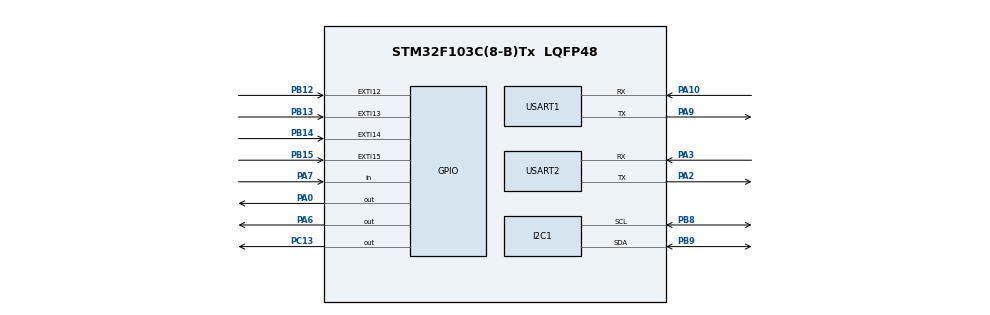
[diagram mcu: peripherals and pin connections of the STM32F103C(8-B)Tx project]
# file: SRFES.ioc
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Dma.Request0=USART1_RX
Dma.Request1=USART1_TX
Dma.Request2=USART2_TX
Dma.Request3=USART2_RX
Dma.USART1_RX.0.Direction=DMA_PERIPH_TO_MEMORY
Dma.USART1_RX.0.Instance=DMA1_Channel5
Dma.USART1_RX.0.MemDataAlignment=DMA_MDATAALIGN_BYTE
Dma.USART1_RX.0.MemInc=DMA_MINC_ENABLE
Dma.USART1_RX.0.Mode=DMA_CIRCULAR
Dma.USART1_RX.0.PeriphDataAlignment=DMA_PDATAALIGN_BYTE
Dma.USART1_RX.0.PeriphInc=DMA_PINC_DISABLE
Dma.USART1_RX.0.Priority=DMA_PRIORITY_HIGH
Dma.USART1_TX.1.Direction=DMA_MEMORY_TO_PERIPH
Dma.USART1_TX.1.Instance=DMA1_Channel4
Dma.USART1_TX.1.MemDataAlignment=DMA_MDATAALIGN_BYTE
Dma.USART1_TX.1.MemInc=DMA_MINC_ENABLE
Dma.USART1_TX.1.Mode=DMA_NORMAL
Dma.USART1_TX.1.PeriphDataAlignment=DMA_PDATAALIGN_BYTE
Dma.USART1_TX.1.PeriphInc=DMA_PINC_DISABLE
Dma.USART1_TX.1.Priority=DMA_PRIORITY_HIGH
Dma.USART2_RX.3.Direction=DMA_PERIPH_TO_MEMORY
Dma.USART2_RX.3.Instance=DMA1_Channel6
Dma.USART2_RX.3.MemDataAlignment=DMA_MDATAALIGN_BYTE
Dma.USART2_RX.3.MemInc=DMA_MINC_ENABLE
Dma.USART2_RX.3.Mode=DMA_CIRCULAR
Dma.USART2_RX.3.PeriphDataAlignment=DMA_PDATAALIGN_BYTE
Dma.USART2_RX.3.PeriphInc=DMA_PINC_DISABLE
Dma.USART2_RX.3.Priority=DMA_PRIORITY_MEDIUM
Dma.USART2_TX.2.Direction=DMA_MEMORY_TO_PERIPH
Dma.USART2_TX.2.Instance=DMA1_Channel7
Dma.USART2_TX.2.MemDataAlignment=DMA_MDATAALIGN_BYTE
Dma.USART2_TX.2.MemInc=DMA_MINC_ENABLE
Dma.USART2_TX.2.Mode=DMA_NORMAL
Dma.USART2_TX.2.PeriphDataAlignment=DMA_PDATAALIGN_BYTE
Dma.USART2_TX.2.PeriphInc=DMA_PINC_DISABLE
Dma.USART2_TX.2.Priority=DMA_PRIORITY_MEDIUM
I2C1.I2C_Mode=I2C_Fast
Mcu.Family=STM32F1
Mcu.Name=STM32F103C(8-B)Tx
Mcu.Package=LQFP48
NVIC.DMA1_Channel4_IRQn=true\:0\:0\:false\:false\:true\:false\:true\:true
NVIC.DMA1_Channel5_IRQn=true\:0\:0\:false\:false\:true\:false\:true\:true
NVIC.DMA1_Channel6_IRQn=true\:0\:0\:false\:false\:true\:false\:true\:true
NVIC.DMA1_Channel7_IRQn=true\:0\:0\:false\:false\:true\:false\:true\:true
NVIC.EXTI15_10_IRQn=true\:1\:0\:true\:false\:true\:true\:true\:true
NVIC.PriorityGroup=NVIC_PRIORITYGROUP_4
NVIC.TIM2_IRQn=true\:2\:0\:true\:false\:true\:true\:true\:true
NVIC.USART1_IRQn=true\:0\:0\:false\:false\:true\:true\:true\:true
NVIC.USART2_IRQn=true\:0\:0\:false\:false\:true\:true\:true\:true
PA0-WKUP.Signal=GPIO_Output
PA10.Mode=Asynchronous
PA10.Signal=USART1_RX
PA13.Mode=Serial_Wire
PA13.Signal=SYS_JTMS-SWDIO
PA14.Mode=Serial_Wire
PA14.Signal=SYS_JTCK-SWCLK
PA2.Mode=Asynchronous
PA2.Signal=USART2_TX
PA3.Mode=Asynchronous
PA3.Signal=USART2_RX
PA6.Signal=GPIO_Output
PA7.GPIO_PuPd=GPIO_PULLUP
PA7.Signal=GPIO_Input
PA9.Mode=Asynchronous
PA9.Signal=USART1_TX
PB12.GPIO_ModeDefaultEXTI=GPIO_MODE_IT_FALLING
PB12.GPIO_PuPd=GPIO_PULLUP
PB12.Signal=GPXTI12
PB13.GPIO_ModeDefaultEXTI=GPIO_MODE_IT_FALLING
PB13.GPIO_PuPd=GPIO_PULLUP
PB13.Signal=GPXTI13
PB14.GPIO_ModeDefaultEXTI=GPIO_MODE_IT_FALLING
PB14.GPIO_PuPd=GPIO_PULLUP
PB14.Signal=GPXTI14
PB15.GPIO_ModeDefaultEXTI=GPIO_MODE_IT_FALLING
PB15.GPIO_PuPd=GPIO_PULLUP
PB15.Signal=GPXTI15
PB8.GPIO_Speed=GPIO_SPEED_FREQ_LOW
PB8.Mode=I2C
PB8.Signal=I2C1_SCL
PB9.GPIO_Speed=GPIO_SPEED_FREQ_LOW
PB9.Mode=I2C
PB9.Signal=I2C1_SDA
PC13-TAMPER-RTC.PinState=GPIO_PIN_SET
PC13-TAMPER-RTC.Signal=GPIO_Output
ProjectManager.HeapSize=0x200
ProjectManager.StackSize=0x400
ProjectManager.TargetToolchain=CMake
RCC.APB1Freq_Value=8000000
RCC.APB2Freq_Value=8000000
TIM2.AutoReloadPreload=TIM_AUTORELOAD_PRELOAD_ENABLE
TIM2.Period=999
TIM2.Prescaler=719
USART1.VirtualMode=VM_ASYNC
USART2.VirtualMode=VM_ASYNC
VP_TIM2_VS_ClockSourceINT.Mode=Internal
board=custom

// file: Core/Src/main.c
/* USER CODE BEGIN Header */
/**
  ******************************************************************************
  * @file           : main.c
  * @brief          : 生鲜结算系统主入口 —— 模块编排器
  *                   所有业务逻辑分散在独立模块中：
  *                     buzzer.c 蜂鸣器 / alarm.c 报警 / led.c 心跳灯
  *                     oled.c 显示 / key.c 按键 / sensor.c 称重
  ******************************************************************************
  */
/* USER CODE END Header */
#include "main.h"
#include "dma.h"
#include "i2c.h"
#include "tim.h"
#include "usart.h"
#include "gpio.h"

/* USER CODE BEGIN Includes */
#include "oled.h"
#include "key.h"
#include "sensor.h"
#include "buzzer.h"
#include "alarm.h"
#include "led.h"
#include "voice.h"
#include "bluetooth.h"
#include <string.h>
/* USER CODE END Includes */

/* USER CODE BEGIN PV */
extern volatile uint32_t sys_tick_ms;
extern volatile uint8_t  task_flag_10ms;
extern volatile uint8_t  task_flag_100ms;
static uint32_t last_bt_upload = 0;
/* USER CODE END PV */

void SystemClock_Config(void);

int main(void)
{

  /* MCU Configuration--------------------------------------------------------*/
      HAL_Init();

  /* Configure the system clock */
  SystemClock_Config();

  /* Initialize all configured peripherals */
  MX_GPIO_Init();
  MX_DMA_Init();
  MX_I2C1_Init();
  MX_USART1_UART_Init();   /* BLE5.4 蓝牙 */
  MX_USART2_UART_Init();   /* ASR-PRO 语音 */
  MX_TIM2_Init();           /* 蜂鸣器 PWM */

  /* USER CODE BEGIN 2 */
  OLED_Setup();
  Boot_Interface_Show();   /* 标题立即可见，进度条+Ready 在 Sensor_Init 之后 */
  oled_force_render = 1;
  OLED_UpdateDisplay(sys_tick_ms);

  Key_Init();
  Buzzer_Init();

  Alarm_Init();
  LED_Init();
  Voice_Init();
  Bluetooth_Init();
  /* USER CODE END 2 */

  /* Infinite loop */
  while (1)
  {

    /* USER CODE BEGIN 3 */
    uint32_t now = sys_tick_ms;

    /* ============================================================
     * 10ms 周期：按键扫描
     * ============================================================ */
    if (task_flag_10ms) {
        task_flag_10ms = 0;
        Key_Scan();
    }

    /* ============================================================
     * 100ms 周期：传感器 → 重量 → 报警
     * ============================================================ */
    if (task_flag_100ms) {
        task_flag_100ms = 0;

        Sensor_Update();
        float w_display = Sensor_GetWeight();
        float w_alarm   = Sensor_GetRawWeight();

        /* 钳位：传感器卸掉重物后可能有微小负漂，强制 ≥0 */
        if (w_display < 0.0f) w_display = 0.0f;
        if (w_alarm   < 0.0f) w_alarm   = 0.0f;

        /* 去皮：净重 = 毛重 - 皮重 */
        float w_net = w_display;
        if (holog.tare_active) {
            w_net -= holog.tare_weight;
            if (w_net < 0.0f) w_net = 0.0f;
        }

        /* 显示重量截取 2 位小数参与总价计算 */
        float w_rounded = (float)((int)(w_net * 100.0f + 0.5f)) / 100.0f;

        float prev = holog.scale.weight;
        holog.scale.weight = w_rounded;
        holog.scale.total_price = holog.scale.unit_price * w_rounded;
        float d = w_rounded - prev;
        if (d < 0) d = -d;
        if (d >= 0.002f) oled_force_render = 1;

        /* 报警使用未经死区的值（净重），以检测小幅抖动 */
        {
            float w_alarm_net = w_alarm;
            if (holog.tare_active) {
                w_alarm_net -= holog.tare_weight;
                if (w_alarm_net < 0.0f) w_alarm_net = 0.0f;
            }
            Alarm_Update(w_alarm_net, now);
        }

        if (Alarm_ShouldEnterPage() && holog.current_page != PAGE_ALARM) {
            uint8_t ow = (Alarm_GetState() == ALARM_OVERWEIGHT);
            uint8_t we = (Alarm_GetState() == ALARM_WEIGHT_ERR);
            OLED_SetAlarmFlags(ow, we);
            holog.prev_page = holog.current_page;
            holog.current_page = PAGE_ALARM;
        }
        if (!Alarm_IsActive() && holog.current_page == PAGE_ALARM) {
            OLED_SetAlarmFlags(0, 0);
            holog.current_page = holog.prev_page;
            holog.edit_mode = 0;
            holog.selected_item = 0;
        }
    }

    /* ============================================================
     * 按键事件消费
     * ============================================================ */
    {
        KeyId id;
        uint8_t is_long;
        while (Key_GetEvent(&id, &is_long)) {
            if (holog.current_page == PAGE_ALARM) {
                /* 报警页：任意键 → 退出页面，报警条件保留 */
                Alarm_Dismiss();
                holog.current_page = holog.prev_page;
                holog.edit_mode = 0;
                holog.selected_item = 0;
                /* 清空剩余按键事件，防止误触下层页面 */
                while (Key_GetEvent(&id, &is_long)) {}
                break;
            } else {
                Buzzer_ShortBeep();
                OLED_HandleKey(id, is_long);
            }
        }
    }

    /* ============================================================
     * 周期刷新
     * ============================================================ */
    OLED_UpdateDisplay(now);
    Buzzer_Process(now,
                   holog.current_page == PAGE_ALARM,
                   Alarm_IsActive());
    LED_Process(now, Alarm_IsActive());
    Voice_Process(now,
                  holog.current_page == PAGE_ALARM,
                  Alarm_GetState() == ALARM_OVERWEIGHT,
                  Alarm_GetState() == ALARM_WEIGHT_ERR);

    /* ============================================================
     * 蓝牙：数据同步 + 定时上报 + 命令处理 + TX 卡死恢复
     * ============================================================ */
    {
        /* 活数据：计算重量/去皮值 */
        float weight   = holog.scale.weight;
        float tare_val = 0.0f;
        if (holog.tare_active) {
            tare_val = holog.tare_weight;
        }
        Bluetooth_SetLiveData(holog.scale.category_idx,
                              holog.scale.unit_price,
                              weight, tare_val,
                              holog.scale.total_price,
                              holog.tare_active ? 1 : 0);

        /* 状态管理：
         * - 报警激活 → 覆盖为报警文本，保存之前的操作状态
         * - 报警结束 → 恢复之前的操作状态（2s 后自动清空）
         * - 无报警   → 操作状态 2s 后自动清空
         */
        if (Alarm_IsActive()) {
            if (!hbt.status_from_alarm) {
                /* 报警首次触发：保存当前操作状态 */
                strncpy(hbt.prev_operation_status, hbt.text_state,
                        sizeof(hbt.prev_operation_status) - 1);
                hbt.prev_operation_status[sizeof(hbt.prev_operation_status) - 1] = '\0';
                hbt.status_from_alarm = 1;
            }
            if (Alarm_GetState() == ALARM_OVERWEIGHT)
                Bluetooth_SetStatus("Overweight! Please lose weight");
            else
                Bluetooth_SetStatus("Weight abnormal! Please measure again");
        } else {
            if (hbt.status_from_alarm) {
                /* 报警结束：恢复之前的操作状态 */
                strncpy(hbt.text_state, hbt.prev_operation_status,
                        sizeof(hbt.text_state) - 1);
                hbt.text_state[sizeof(hbt.text_state) - 1] = '\0';
                hbt.status_from_alarm = 0;
                if (hbt.text_state[0] != '\0') {
                    /* 有操作状态：重置 2s 计时 */
                    hbt.status_set_time = now;
                } else {
                    /* 无操作状态：清空计时 */
                    hbt.status_set_time = 0;
                }
            } else if (hbt.status_set_time != 0 &&
                       now - hbt.status_set_time >= 2000) {
                /* 操作状态 2s 后自动清空 */
                Bluetooth_SetStatus("");
                hbt.status_set_time = 0;
            }
        }

        if (hbt.immediate_upload || now - last_bt_upload >= BT_PERIOD_MS) {
            hbt.immediate_upload = 0;
            last_bt_upload = now;
            Bluetooth_SendData();
        }

        Bluetooth_ProcessCommand();
        Bluetooth_CheckTXStuck(now);
    }
  }
  /* USER CODE END 3 */
}

void SystemClock_Config(void)
{
  RCC_OscInitTypeDef RCC_OscInitStruct = {0};
  RCC_ClkInitTypeDef RCC_ClkInitStruct = {0};

  RCC_OscInitStruct.OscillatorType = RCC_OSCILLATORTYPE_HSE;
  RCC_OscInitStruct.HSEState = RCC_HSE_ON;
  RCC_OscInitStruct.HSEPredivValue = RCC_HSE_PREDIV_DIV1;
  RCC_OscInitStruct.HSIState = RCC_HSI_ON;
  RCC_OscInitStruct.PLL.PLLState = RCC_PLL_ON;
  RCC_OscInitStruct.PLL.PLLSource = RCC_PLLSOURCE_HSE;
  RCC_OscInitStruct.PLL.PLLMUL = RCC_PLL_MUL9;
  if (HAL_RCC_OscConfig(&RCC_OscInitStruct) != HAL_OK)
  {
    Error_Handler();
  }

  RCC_ClkInitStruct.ClockType = RCC_CLOCKTYPE_HCLK|RCC_CLOCKTYPE_SYSCLK
                              |RCC_CLOCKTYPE_PCLK1|RCC_CLOCKTYPE_PCLK2;
  RCC_ClkInitStruct.SYSCLKSource = RCC_SYSCLKSOURCE_PLLCLK;
  RCC_ClkInitStruct.AHBCLKDivider = RCC_SYSCLK_DIV1;
  RCC_ClkInitStruct.APB1CLKDivider = RCC_HCLK_DIV1;
  RCC_ClkInitStruct.APB2CLKDivider = RCC_HCLK_DIV1;

  if (HAL_RCC_ClockConfig(&RCC_ClkInitStruct, FLASH_LATENCY_2) != HAL_OK)
  {
    Error_Handler();
  }
}

void Error_Handler(void)
{
  __disable_irq();
  while (1)
  {
  }
}
